VERSION 5.8 ;
BUSBITCHARS "[]" ;
DIVIDERCHAR "/" ;
UNITS
    DATABASE MICRONS 1000 ;
END UNITS

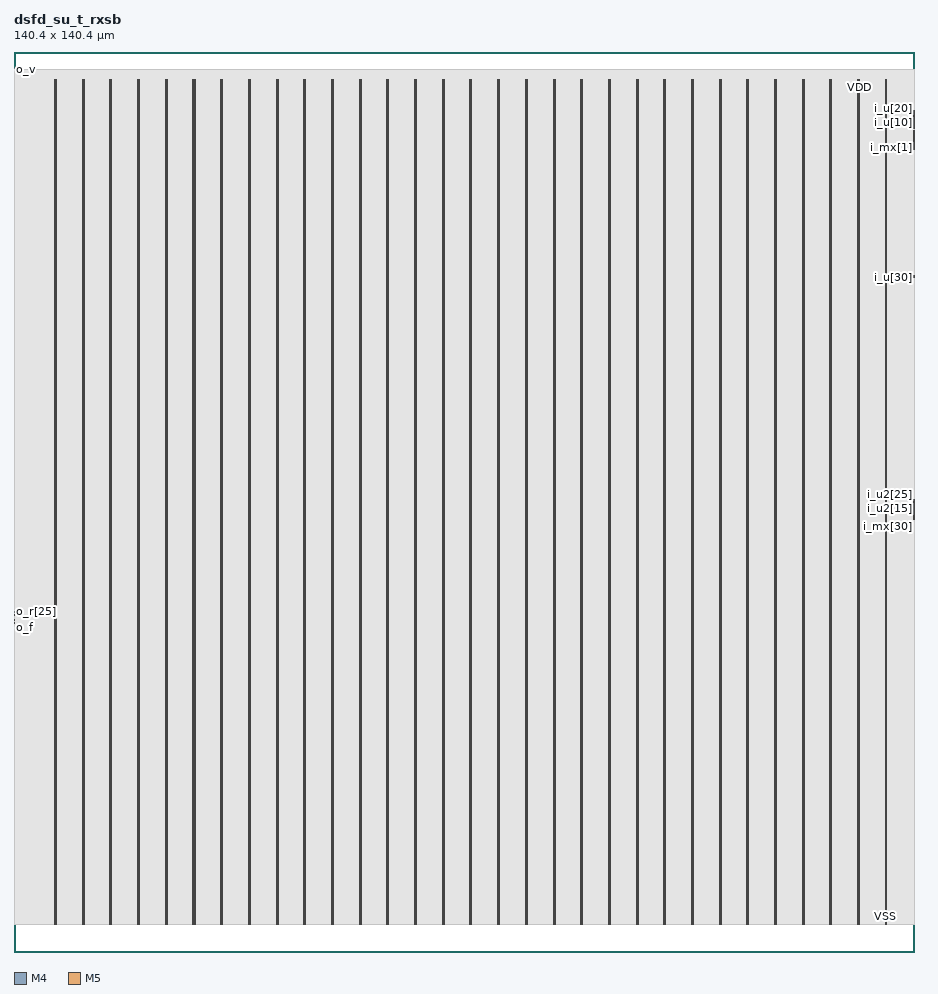
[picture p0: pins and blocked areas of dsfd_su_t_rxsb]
MACRO dsfd_su_t_rxsb
  FOREIGN dsfd_su_t_rxsb 0 0 ;
  CLASS BLOCK ;
  SIZE 140.4 BY 140.4 ;
  PIN ck
    DIRECTION INPUT ;
    USE SIGNAL ;
    PORT
      LAYER M4 ;
        RECT  140.316 125.136 140.4 125.16 ;
    END
  END ck
  PIN i_f
    DIRECTION INPUT ;
    USE SIGNAL ;
    PORT
      LAYER M4 ;
        RECT  140.316 125.232 140.4 125.256 ;
    END
  END i_f
  PIN i_mx[0]
    DIRECTION INPUT ;
    USE SIGNAL ;
    PORT
      LAYER M4 ;
        RECT  140.316 125.328 140.4 125.352 ;
    END
  END i_mx[0]
  PIN i_mx[10]
    DIRECTION INPUT ;
    USE SIGNAL ;
    PORT
      LAYER M4 ;
        RECT  140.316 126.288 140.4 126.312 ;
    END
  END i_mx[10]
  PIN i_mx[11]
    DIRECTION INPUT ;
    USE SIGNAL ;
    PORT
      LAYER M4 ;
        RECT  140.316 126.384 140.4 126.408 ;
    END
  END i_mx[11]
  PIN i_mx[12]
    DIRECTION INPUT ;
    USE SIGNAL ;
    PORT
      LAYER M4 ;
        RECT  140.316 126.48 140.4 126.504 ;
    END
  END i_mx[12]
  PIN i_mx[13]
    DIRECTION INPUT ;
    USE SIGNAL ;
    PORT
      LAYER M4 ;
        RECT  140.316 126.576 140.4 126.6 ;
    END
  END i_mx[13]
  PIN i_mx[14]
    DIRECTION INPUT ;
    USE SIGNAL ;
    PORT
      LAYER M4 ;
        RECT  140.316 126.672 140.4 126.696 ;
    END
  END i_mx[14]
  PIN i_mx[15]
    DIRECTION INPUT ;
    USE SIGNAL ;
    PORT
      LAYER M4 ;
        RECT  140.316 126.768 140.4 126.792 ;
    END
  END i_mx[15]
  PIN i_mx[16]
    DIRECTION INPUT ;
    USE SIGNAL ;
    PORT
      LAYER M4 ;
        RECT  140.316 126.864 140.4 126.888 ;
    END
  END i_mx[16]
  PIN i_mx[17]
    DIRECTION INPUT ;
    USE SIGNAL ;
    PORT
      LAYER M4 ;
        RECT  140.316 126.96 140.4 126.984 ;
    END
  END i_mx[17]
  PIN i_mx[18]
    DIRECTION INPUT ;
    USE SIGNAL ;
    PORT
      LAYER M4 ;
        RECT  140.316 127.056 140.4 127.08 ;
    END
  END i_mx[18]
  PIN i_mx[19]
    DIRECTION INPUT ;
    USE SIGNAL ;
    PORT
      LAYER M4 ;
        RECT  140.316 127.152 140.4 127.176 ;
    END
  END i_mx[19]
  PIN i_mx[1]
    DIRECTION INPUT ;
    USE SIGNAL ;
    PORT
      LAYER M4 ;
        RECT  140.316 125.424 140.4 125.448 ;
    END
  END i_mx[1]
  PIN i_mx[20]
    DIRECTION INPUT ;
    USE SIGNAL ;
    PORT
      LAYER M4 ;
        RECT  140.316 127.248 140.4 127.272 ;
    END
  END i_mx[20]
  PIN i_mx[21]
    DIRECTION INPUT ;
    USE SIGNAL ;
    PORT
      LAYER M4 ;
        RECT  140.316 127.344 140.4 127.368 ;
    END
  END i_mx[21]
  PIN i_mx[22]
    DIRECTION INPUT ;
    USE SIGNAL ;
    PORT
      LAYER M4 ;
        RECT  140.316 127.44 140.4 127.464 ;
    END
  END i_mx[22]
  PIN i_mx[23]
    DIRECTION INPUT ;
    USE SIGNAL ;
    PORT
      LAYER M4 ;
        RECT  140.316 127.536 140.4 127.56 ;
    END
  END i_mx[23]
  PIN i_mx[24]
    DIRECTION INPUT ;
    USE SIGNAL ;
    PORT
      LAYER M4 ;
        RECT  140.316 127.632 140.4 127.656 ;
    END
  END i_mx[24]
  PIN i_mx[25]
    DIRECTION INPUT ;
    USE SIGNAL ;
    PORT
      LAYER M4 ;
        RECT  140.316 127.728 140.4 127.752 ;
    END
  END i_mx[25]
  PIN i_mx[26]
    DIRECTION INPUT ;
    USE SIGNAL ;
    PORT
      LAYER M4 ;
        RECT  140.316 127.824 140.4 127.848 ;
    END
  END i_mx[26]
  PIN i_mx[27]
    DIRECTION INPUT ;
    USE SIGNAL ;
    PORT
      LAYER M4 ;
        RECT  140.316 127.92 140.4 127.944 ;
    END
  END i_mx[27]
  PIN i_mx[28]
    DIRECTION INPUT ;
    USE SIGNAL ;
    PORT
      LAYER M4 ;
        RECT  140.316 128.016 140.4 128.04 ;
    END
  END i_mx[28]
  PIN i_mx[29]
    DIRECTION INPUT ;
    USE SIGNAL ;
    PORT
      LAYER M4 ;
        RECT  140.316 128.112 140.4 128.136 ;
    END
  END i_mx[29]
  PIN i_mx[2]
    DIRECTION INPUT ;
    USE SIGNAL ;
    PORT
      LAYER M4 ;
        RECT  140.316 125.52 140.4 125.544 ;
    END
  END i_mx[2]
  PIN i_mx[30]
    DIRECTION INPUT ;
    USE SIGNAL ;
    PORT
      LAYER M4 ;
        RECT  140.316 67.536 140.4 67.56 ;
    END
  END i_mx[30]
  PIN i_mx[31]
    DIRECTION INPUT ;
    USE SIGNAL ;
    PORT
      LAYER M4 ;
        RECT  140.316 67.632 140.4 67.656 ;
    END
  END i_mx[31]
  PIN i_mx[3]
    DIRECTION INPUT ;
    USE SIGNAL ;
    PORT
      LAYER M4 ;
        RECT  140.316 125.616 140.4 125.64 ;
    END
  END i_mx[3]
  PIN i_mx[4]
    DIRECTION INPUT ;
    USE SIGNAL ;
    PORT
      LAYER M4 ;
        RECT  140.316 125.712 140.4 125.736 ;
    END
  END i_mx[4]
  PIN i_mx[5]
    DIRECTION INPUT ;
    USE SIGNAL ;
    PORT
      LAYER M4 ;
        RECT  140.316 125.808 140.4 125.832 ;
    END
  END i_mx[5]
  PIN i_mx[6]
    DIRECTION INPUT ;
    USE SIGNAL ;
    PORT
      LAYER M4 ;
        RECT  140.316 125.904 140.4 125.928 ;
    END
  END i_mx[6]
  PIN i_mx[7]
    DIRECTION INPUT ;
    USE SIGNAL ;
    PORT
      LAYER M4 ;
        RECT  140.316 126 140.4 126.024 ;
    END
  END i_mx[7]
  PIN i_mx[8]
    DIRECTION INPUT ;
    USE SIGNAL ;
    PORT
      LAYER M4 ;
        RECT  140.316 126.096 140.4 126.12 ;
    END
  END i_mx[8]
  PIN i_mx[9]
    DIRECTION INPUT ;
    USE SIGNAL ;
    PORT
      LAYER M4 ;
        RECT  140.316 126.192 140.4 126.216 ;
    END
  END i_mx[9]
  PIN i_u2[0]
    DIRECTION INPUT ;
    USE SIGNAL ;
    PORT
      LAYER M4 ;
        RECT  140.316 67.728 140.4 67.752 ;
    END
  END i_u2[0]
  PIN i_u2[10]
    DIRECTION INPUT ;
    USE SIGNAL ;
    PORT
      LAYER M4 ;
        RECT  140.316 68.688 140.4 68.712 ;
    END
  END i_u2[10]
  PIN i_u2[11]
    DIRECTION INPUT ;
    USE SIGNAL ;
    PORT
      LAYER M4 ;
        RECT  140.316 68.784 140.4 68.808 ;
    END
  END i_u2[11]
  PIN i_u2[12]
    DIRECTION INPUT ;
    USE SIGNAL ;
    PORT
      LAYER M4 ;
        RECT  140.316 68.88 140.4 68.904 ;
    END
  END i_u2[12]
  PIN i_u2[13]
    DIRECTION INPUT ;
    USE SIGNAL ;
    PORT
      LAYER M4 ;
        RECT  140.316 68.976 140.4 69 ;
    END
  END i_u2[13]
  PIN i_u2[14]
    DIRECTION INPUT ;
    USE SIGNAL ;
    PORT
      LAYER M4 ;
        RECT  140.316 69.072 140.4 69.096 ;
    END
  END i_u2[14]
  PIN i_u2[15]
    DIRECTION INPUT ;
    USE SIGNAL ;
    PORT
      LAYER M4 ;
        RECT  140.316 69.168 140.4 69.192 ;
    END
  END i_u2[15]
  PIN i_u2[16]
    DIRECTION INPUT ;
    USE SIGNAL ;
    PORT
      LAYER M4 ;
        RECT  140.316 69.264 140.4 69.288 ;
    END
  END i_u2[16]
  PIN i_u2[17]
    DIRECTION INPUT ;
    USE SIGNAL ;
    PORT
      LAYER M4 ;
        RECT  140.316 69.36 140.4 69.384 ;
    END
  END i_u2[17]
  PIN i_u2[18]
    DIRECTION INPUT ;
    USE SIGNAL ;
    PORT
      LAYER M4 ;
        RECT  140.316 69.456 140.4 69.48 ;
    END
  END i_u2[18]
  PIN i_u2[19]
    DIRECTION INPUT ;
    USE SIGNAL ;
    PORT
      LAYER M4 ;
        RECT  140.316 69.552 140.4 69.576 ;
    END
  END i_u2[19]
  PIN i_u2[1]
    DIRECTION INPUT ;
    USE SIGNAL ;
    PORT
      LAYER M4 ;
        RECT  140.316 67.824 140.4 67.848 ;
    END
  END i_u2[1]
  PIN i_u2[20]
    DIRECTION INPUT ;
    USE SIGNAL ;
    PORT
      LAYER M4 ;
        RECT  140.316 69.648 140.4 69.672 ;
    END
  END i_u2[20]
  PIN i_u2[21]
    DIRECTION INPUT ;
    USE SIGNAL ;
    PORT
      LAYER M4 ;
        RECT  140.316 69.744 140.4 69.768 ;
    END
  END i_u2[21]
  PIN i_u2[22]
    DIRECTION INPUT ;
    USE SIGNAL ;
    PORT
      LAYER M4 ;
        RECT  140.316 69.84 140.4 69.864 ;
    END
  END i_u2[22]
  PIN i_u2[23]
    DIRECTION INPUT ;
    USE SIGNAL ;
    PORT
      LAYER M4 ;
        RECT  140.316 69.936 140.4 69.96 ;
    END
  END i_u2[23]
  PIN i_u2[24]
    DIRECTION INPUT ;
    USE SIGNAL ;
    PORT
      LAYER M4 ;
        RECT  140.316 70.032 140.4 70.056 ;
    END
  END i_u2[24]
  PIN i_u2[25]
    DIRECTION INPUT ;
    USE SIGNAL ;
    PORT
      LAYER M4 ;
        RECT  140.316 70.128 140.4 70.152 ;
    END
  END i_u2[25]
  PIN i_u2[26]
    DIRECTION INPUT ;
    USE SIGNAL ;
    PORT
      LAYER M4 ;
        RECT  140.316 70.224 140.4 70.248 ;
    END
  END i_u2[26]
  PIN i_u2[27]
    DIRECTION INPUT ;
    USE SIGNAL ;
    PORT
      LAYER M4 ;
        RECT  140.316 70.32 140.4 70.344 ;
    END
  END i_u2[27]
  PIN i_u2[28]
    DIRECTION INPUT ;
    USE SIGNAL ;
    PORT
      LAYER M4 ;
        RECT  140.316 70.416 140.4 70.44 ;
    END
  END i_u2[28]
  PIN i_u2[29]
    DIRECTION INPUT ;
    USE SIGNAL ;
    PORT
      LAYER M4 ;
        RECT  140.316 70.512 140.4 70.536 ;
    END
  END i_u2[29]
  PIN i_u2[2]
    DIRECTION INPUT ;
    USE SIGNAL ;
    PORT
      LAYER M4 ;
        RECT  140.316 67.92 140.4 67.944 ;
    END
  END i_u2[2]
  PIN i_u2[30]
    DIRECTION INPUT ;
    USE SIGNAL ;
    PORT
      LAYER M4 ;
        RECT  140.316 128.208 140.4 128.232 ;
    END
  END i_u2[30]
  PIN i_u2[3]
    DIRECTION INPUT ;
    USE SIGNAL ;
    PORT
      LAYER M4 ;
        RECT  140.316 68.016 140.4 68.04 ;
    END
  END i_u2[3]
  PIN i_u2[4]
    DIRECTION INPUT ;
    USE SIGNAL ;
    PORT
      LAYER M4 ;
        RECT  140.316 68.112 140.4 68.136 ;
    END
  END i_u2[4]
  PIN i_u2[5]
    DIRECTION INPUT ;
    USE SIGNAL ;
    PORT
      LAYER M4 ;
        RECT  140.316 68.208 140.4 68.232 ;
    END
  END i_u2[5]
  PIN i_u2[6]
    DIRECTION INPUT ;
    USE SIGNAL ;
    PORT
      LAYER M4 ;
        RECT  140.316 68.304 140.4 68.328 ;
    END
  END i_u2[6]
  PIN i_u2[7]
    DIRECTION INPUT ;
    USE SIGNAL ;
    PORT
      LAYER M4 ;
        RECT  140.316 68.4 140.4 68.424 ;
    END
  END i_u2[7]
  PIN i_u2[8]
    DIRECTION INPUT ;
    USE SIGNAL ;
    PORT
      LAYER M4 ;
        RECT  140.316 68.496 140.4 68.52 ;
    END
  END i_u2[8]
  PIN i_u2[9]
    DIRECTION INPUT ;
    USE SIGNAL ;
    PORT
      LAYER M4 ;
        RECT  140.316 68.592 140.4 68.616 ;
    END
  END i_u2[9]
  PIN i_u[0]
    DIRECTION INPUT ;
    USE SIGNAL ;
    PORT
      LAYER M4 ;
        RECT  140.316 128.4 140.4 128.424 ;
    END
  END i_u[0]
  PIN i_u[10]
    DIRECTION INPUT ;
    USE SIGNAL ;
    PORT
      LAYER M4 ;
        RECT  140.316 129.36 140.4 129.384 ;
    END
  END i_u[10]
  PIN i_u[11]
    DIRECTION INPUT ;
    USE SIGNAL ;
    PORT
      LAYER M4 ;
        RECT  140.316 129.456 140.4 129.48 ;
    END
  END i_u[11]
  PIN i_u[12]
    DIRECTION INPUT ;
    USE SIGNAL ;
    PORT
      LAYER M4 ;
        RECT  140.316 129.552 140.4 129.576 ;
    END
  END i_u[12]
  PIN i_u[13]
    DIRECTION INPUT ;
    USE SIGNAL ;
    PORT
      LAYER M4 ;
        RECT  140.316 129.648 140.4 129.672 ;
    END
  END i_u[13]
  PIN i_u[14]
    DIRECTION INPUT ;
    USE SIGNAL ;
    PORT
      LAYER M4 ;
        RECT  140.316 129.744 140.4 129.768 ;
    END
  END i_u[14]
  PIN i_u[15]
    DIRECTION INPUT ;
    USE SIGNAL ;
    PORT
      LAYER M4 ;
        RECT  140.316 129.84 140.4 129.864 ;
    END
  END i_u[15]
  PIN i_u[16]
    DIRECTION INPUT ;
    USE SIGNAL ;
    PORT
      LAYER M4 ;
        RECT  140.316 129.936 140.4 129.96 ;
    END
  END i_u[16]
  PIN i_u[17]
    DIRECTION INPUT ;
    USE SIGNAL ;
    PORT
      LAYER M4 ;
        RECT  140.316 130.032 140.4 130.056 ;
    END
  END i_u[17]
  PIN i_u[18]
    DIRECTION INPUT ;
    USE SIGNAL ;
    PORT
      LAYER M4 ;
        RECT  140.316 130.128 140.4 130.152 ;
    END
  END i_u[18]
  PIN i_u[19]
    DIRECTION INPUT ;
    USE SIGNAL ;
    PORT
      LAYER M4 ;
        RECT  140.316 130.224 140.4 130.248 ;
    END
  END i_u[19]
  PIN i_u[1]
    DIRECTION INPUT ;
    USE SIGNAL ;
    PORT
      LAYER M4 ;
        RECT  140.316 128.496 140.4 128.52 ;
    END
  END i_u[1]
  PIN i_u[20]
    DIRECTION INPUT ;
    USE SIGNAL ;
    PORT
      LAYER M4 ;
        RECT  140.316 130.32 140.4 130.344 ;
    END
  END i_u[20]
  PIN i_u[21]
    DIRECTION INPUT ;
    USE SIGNAL ;
    PORT
      LAYER M4 ;
        RECT  140.316 130.416 140.4 130.44 ;
    END
  END i_u[21]
  PIN i_u[22]
    DIRECTION INPUT ;
    USE SIGNAL ;
    PORT
      LAYER M4 ;
        RECT  140.316 130.512 140.4 130.536 ;
    END
  END i_u[22]
  PIN i_u[23]
    DIRECTION INPUT ;
    USE SIGNAL ;
    PORT
      LAYER M4 ;
        RECT  140.316 130.608 140.4 130.632 ;
    END
  END i_u[23]
  PIN i_u[24]
    DIRECTION INPUT ;
    USE SIGNAL ;
    PORT
      LAYER M4 ;
        RECT  140.316 130.704 140.4 130.728 ;
    END
  END i_u[24]
  PIN i_u[25]
    DIRECTION INPUT ;
    USE SIGNAL ;
    PORT
      LAYER M4 ;
        RECT  140.316 130.8 140.4 130.824 ;
    END
  END i_u[25]
  PIN i_u[26]
    DIRECTION INPUT ;
    USE SIGNAL ;
    PORT
      LAYER M4 ;
        RECT  140.316 130.896 140.4 130.92 ;
    END
  END i_u[26]
  PIN i_u[27]
    DIRECTION INPUT ;
    USE SIGNAL ;
    PORT
      LAYER M4 ;
        RECT  140.316 130.992 140.4 131.016 ;
    END
  END i_u[27]
  PIN i_u[28]
    DIRECTION INPUT ;
    USE SIGNAL ;
    PORT
      LAYER M4 ;
        RECT  140.316 131.088 140.4 131.112 ;
    END
  END i_u[28]
  PIN i_u[29]
    DIRECTION INPUT ;
    USE SIGNAL ;
    PORT
      LAYER M4 ;
        RECT  140.316 131.184 140.4 131.208 ;
    END
  END i_u[29]
  PIN i_u[2]
    DIRECTION INPUT ;
    USE SIGNAL ;
    PORT
      LAYER M4 ;
        RECT  140.316 128.592 140.4 128.616 ;
    END
  END i_u[2]
  PIN i_u[30]
    DIRECTION INPUT ;
    USE SIGNAL ;
    PORT
      LAYER M4 ;
        RECT  140.316 105.168 140.4 105.192 ;
    END
  END i_u[30]
  PIN i_u[3]
    DIRECTION INPUT ;
    USE SIGNAL ;
    PORT
      LAYER M4 ;
        RECT  140.316 128.688 140.4 128.712 ;
    END
  END i_u[3]
  PIN i_u[4]
    DIRECTION INPUT ;
    USE SIGNAL ;
    PORT
      LAYER M4 ;
        RECT  140.316 128.784 140.4 128.808 ;
    END
  END i_u[4]
  PIN i_u[5]
    DIRECTION INPUT ;
    USE SIGNAL ;
    PORT
      LAYER M4 ;
        RECT  140.316 128.88 140.4 128.904 ;
    END
  END i_u[5]
  PIN i_u[6]
    DIRECTION INPUT ;
    USE SIGNAL ;
    PORT
      LAYER M4 ;
        RECT  140.316 128.976 140.4 129 ;
    END
  END i_u[6]
  PIN i_u[7]
    DIRECTION INPUT ;
    USE SIGNAL ;
    PORT
      LAYER M4 ;
        RECT  140.316 129.072 140.4 129.096 ;
    END
  END i_u[7]
  PIN i_u[8]
    DIRECTION INPUT ;
    USE SIGNAL ;
    PORT
      LAYER M4 ;
        RECT  140.316 129.168 140.4 129.192 ;
    END
  END i_u[8]
  PIN i_u[9]
    DIRECTION INPUT ;
    USE SIGNAL ;
    PORT
      LAYER M4 ;
        RECT  140.316 129.264 140.4 129.288 ;
    END
  END i_u[9]
  PIN i_v
    DIRECTION INPUT ;
    USE SIGNAL ;
    PORT
      LAYER M4 ;
        RECT  140.316 105.36 140.4 105.384 ;
    END
  END i_v
  PIN o_f
    DIRECTION OUTPUT ;
    USE SIGNAL ;
    PORT
      LAYER M4 ;
        RECT  0 50.64 0.084 50.664 ;
    END
  END o_f
  PIN o_r[0]
    DIRECTION OUTPUT ;
    USE SIGNAL ;
    PORT
      LAYER M4 ;
        RECT  0 50.736 0.084 50.76 ;
    END
  END o_r[0]
  PIN o_r[10]
    DIRECTION OUTPUT ;
    USE SIGNAL ;
    PORT
      LAYER M4 ;
        RECT  0 51.696 0.084 51.72 ;
    END
  END o_r[10]
  PIN o_r[11]
    DIRECTION OUTPUT ;
    USE SIGNAL ;
    PORT
      LAYER M4 ;
        RECT  0 51.792 0.084 51.816 ;
    END
  END o_r[11]
  PIN o_r[12]
    DIRECTION OUTPUT ;
    USE SIGNAL ;
    PORT
      LAYER M4 ;
        RECT  0 51.888 0.084 51.912 ;
    END
  END o_r[12]
  PIN o_r[13]
    DIRECTION OUTPUT ;
    USE SIGNAL ;
    PORT
      LAYER M4 ;
        RECT  0 51.984 0.084 52.008 ;
    END
  END o_r[13]
  PIN o_r[14]
    DIRECTION OUTPUT ;
    USE SIGNAL ;
    PORT
      LAYER M4 ;
        RECT  0 52.08 0.084 52.104 ;
    END
  END o_r[14]
  PIN o_r[15]
    DIRECTION OUTPUT ;
    USE SIGNAL ;
    PORT
      LAYER M4 ;
        RECT  0 52.176 0.084 52.2 ;
    END
  END o_r[15]
  PIN o_r[16]
    DIRECTION OUTPUT ;
    USE SIGNAL ;
    PORT
      LAYER M4 ;
        RECT  0 52.272 0.084 52.296 ;
    END
  END o_r[16]
  PIN o_r[17]
    DIRECTION OUTPUT ;
    USE SIGNAL ;
    PORT
      LAYER M4 ;
        RECT  0 52.368 0.084 52.392 ;
    END
  END o_r[17]
  PIN o_r[18]
    DIRECTION OUTPUT ;
    USE SIGNAL ;
    PORT
      LAYER M4 ;
        RECT  0 52.464 0.084 52.488 ;
    END
  END o_r[18]
  PIN o_r[19]
    DIRECTION OUTPUT ;
    USE SIGNAL ;
    PORT
      LAYER M4 ;
        RECT  0 52.56 0.084 52.584 ;
    END
  END o_r[19]
  PIN o_r[1]
    DIRECTION OUTPUT ;
    USE SIGNAL ;
    PORT
      LAYER M4 ;
        RECT  0 50.832 0.084 50.856 ;
    END
  END o_r[1]
  PIN o_r[20]
    DIRECTION OUTPUT ;
    USE SIGNAL ;
    PORT
      LAYER M4 ;
        RECT  0 52.656 0.084 52.68 ;
    END
  END o_r[20]
  PIN o_r[21]
    DIRECTION OUTPUT ;
    USE SIGNAL ;
    PORT
      LAYER M4 ;
        RECT  0 52.752 0.084 52.776 ;
    END
  END o_r[21]
  PIN o_r[22]
    DIRECTION OUTPUT ;
    USE SIGNAL ;
    PORT
      LAYER M4 ;
        RECT  0 52.848 0.084 52.872 ;
    END
  END o_r[22]
  PIN o_r[23]
    DIRECTION OUTPUT ;
    USE SIGNAL ;
    PORT
      LAYER M4 ;
        RECT  0 52.944 0.084 52.968 ;
    END
  END o_r[23]
  PIN o_r[24]
    DIRECTION OUTPUT ;
    USE SIGNAL ;
    PORT
      LAYER M4 ;
        RECT  0 53.04 0.084 53.064 ;
    END
  END o_r[24]
  PIN o_r[25]
    DIRECTION OUTPUT ;
    USE SIGNAL ;
    PORT
      LAYER M4 ;
        RECT  0 53.136 0.084 53.16 ;
    END
  END o_r[25]
  PIN o_r[26]
    DIRECTION OUTPUT ;
    USE SIGNAL ;
    PORT
      LAYER M4 ;
        RECT  0 53.232 0.084 53.256 ;
    END
  END o_r[26]
  PIN o_r[27]
    DIRECTION OUTPUT ;
    USE SIGNAL ;
    PORT
      LAYER M4 ;
        RECT  0 53.328 0.084 53.352 ;
    END
  END o_r[27]
  PIN o_r[28]
    DIRECTION OUTPUT ;
    USE SIGNAL ;
    PORT
      LAYER M4 ;
        RECT  0 53.424 0.084 53.448 ;
    END
  END o_r[28]
  PIN o_r[29]
    DIRECTION OUTPUT ;
    USE SIGNAL ;
    PORT
      LAYER M4 ;
        RECT  0 53.52 0.084 53.544 ;
    END
  END o_r[29]
  PIN o_r[2]
    DIRECTION OUTPUT ;
    USE SIGNAL ;
    PORT
      LAYER M4 ;
        RECT  0 50.928 0.084 50.952 ;
    END
  END o_r[2]
  PIN o_r[30]
    DIRECTION OUTPUT ;
    USE SIGNAL ;
    PORT
      LAYER M4 ;
        RECT  0 53.616 0.084 53.64 ;
    END
  END o_r[30]
  PIN o_r[3]
    DIRECTION OUTPUT ;
    USE SIGNAL ;
    PORT
      LAYER M4 ;
        RECT  0 51.024 0.084 51.048 ;
    END
  END o_r[3]
  PIN o_r[4]
    DIRECTION OUTPUT ;
    USE SIGNAL ;
    PORT
      LAYER M4 ;
        RECT  0 51.12 0.084 51.144 ;
    END
  END o_r[4]
  PIN o_r[5]
    DIRECTION OUTPUT ;
    USE SIGNAL ;
    PORT
      LAYER M4 ;
        RECT  0 51.216 0.084 51.24 ;
    END
  END o_r[5]
  PIN o_r[6]
    DIRECTION OUTPUT ;
    USE SIGNAL ;
    PORT
      LAYER M4 ;
        RECT  0 51.312 0.084 51.336 ;
    END
  END o_r[6]
  PIN o_r[7]
    DIRECTION OUTPUT ;
    USE SIGNAL ;
    PORT
      LAYER M4 ;
        RECT  0 51.408 0.084 51.432 ;
    END
  END o_r[7]
  PIN o_r[8]
    DIRECTION OUTPUT ;
    USE SIGNAL ;
    PORT
      LAYER M4 ;
        RECT  0 51.504 0.084 51.528 ;
    END
  END o_r[8]
  PIN o_r[9]
    DIRECTION OUTPUT ;
    USE SIGNAL ;
    PORT
      LAYER M4 ;
        RECT  0 51.6 0.084 51.624 ;
    END
  END o_r[9]
  PIN o_v
    DIRECTION OUTPUT ;
    USE SIGNAL ;
    PORT
      LAYER M4 ;
        RECT  0 137.712 0.084 137.736 ;
    END
  END o_v
  PIN rst
    DIRECTION INPUT ;
    USE SIGNAL ;
    PORT
      LAYER M4 ;
        RECT  140.316 105.456 140.4 105.48 ;
    END
  END rst
  PIN VDD
    DIRECTION INOUT ;
    USE POWER ;
    PORT
      LAYER M5 ;
        RECT  131.796 4.311 131.916 136.089 ;
        RECT  127.476 4.311 127.596 136.089 ;
        RECT  123.156 4.311 123.276 136.089 ;
        RECT  118.836 4.311 118.956 136.089 ;
        RECT  114.516 4.311 114.636 136.089 ;
        RECT  110.196 4.311 110.316 136.089 ;
        RECT  105.876 4.311 105.996 136.089 ;
        RECT  101.556 4.311 101.676 136.089 ;
        RECT  97.236 4.311 97.356 136.089 ;
        RECT  92.916 4.311 93.036 136.089 ;
        RECT  88.596 4.311 88.716 136.089 ;
        RECT  84.276 4.311 84.396 136.089 ;
        RECT  79.956 4.311 80.076 136.089 ;
        RECT  75.636 4.311 75.756 136.089 ;
        RECT  71.316 4.311 71.436 136.089 ;
        RECT  66.996 4.311 67.116 136.089 ;
        RECT  62.676 4.311 62.796 136.089 ;
        RECT  58.356 4.311 58.476 136.089 ;
        RECT  54.036 4.311 54.156 136.089 ;
        RECT  49.716 4.311 49.836 136.089 ;
        RECT  45.396 4.311 45.516 136.089 ;
        RECT  41.076 4.311 41.196 136.089 ;
        RECT  36.756 4.311 36.876 136.089 ;
        RECT  32.436 4.311 32.556 136.089 ;
        RECT  28.116 4.311 28.236 136.089 ;
        RECT  23.796 4.311 23.916 136.089 ;
        RECT  19.476 4.311 19.596 136.089 ;
        RECT  15.156 4.311 15.276 136.089 ;
        RECT  10.836 4.311 10.956 136.089 ;
        RECT  6.516 4.311 6.636 136.089 ;
    END
  END VDD
  PIN VSS
    DIRECTION INOUT ;
    USE GROUND ;
    PORT
      LAYER M5 ;
        RECT  135.924 4.297 136.044 136.103 ;
        RECT  131.604 4.297 131.724 136.103 ;
        RECT  127.284 4.297 127.404 136.103 ;
        RECT  122.964 4.297 123.084 136.103 ;
        RECT  118.644 4.297 118.764 136.103 ;
        RECT  114.324 4.297 114.444 136.103 ;
        RECT  110.004 4.297 110.124 136.103 ;
        RECT  105.684 4.297 105.804 136.103 ;
        RECT  101.364 4.297 101.484 136.103 ;
        RECT  97.044 4.297 97.164 136.103 ;
        RECT  92.724 4.297 92.844 136.103 ;
        RECT  88.404 4.297 88.524 136.103 ;
        RECT  84.084 4.297 84.204 136.103 ;
        RECT  79.764 4.297 79.884 136.103 ;
        RECT  75.444 4.297 75.564 136.103 ;
        RECT  71.124 4.297 71.244 136.103 ;
        RECT  66.804 4.297 66.924 136.103 ;
        RECT  62.484 4.297 62.604 136.103 ;
        RECT  58.164 4.297 58.284 136.103 ;
        RECT  53.844 4.297 53.964 136.103 ;
        RECT  49.524 4.297 49.644 136.103 ;
        RECT  45.204 4.297 45.324 136.103 ;
        RECT  40.884 4.297 41.004 136.103 ;
        RECT  36.564 4.297 36.684 136.103 ;
        RECT  32.244 4.297 32.364 136.103 ;
        RECT  27.924 4.297 28.044 136.103 ;
        RECT  23.604 4.297 23.724 136.103 ;
        RECT  19.284 4.297 19.404 136.103 ;
        RECT  14.964 4.297 15.084 136.103 ;
        RECT  10.644 4.297 10.764 136.103 ;
        RECT  6.324 4.297 6.444 136.103 ;
    END
  END VSS
  OBS
    LAYER RVTN ;
     RECT  0 4.261 140.4 137.741 ;
    LAYER RVTP ;
     RECT  0 4.261 140.4 137.741 ;
    LAYER M1 ;
     RECT  0 4.261 140.4 137.741 ;
    LAYER M2 ;
     RECT  0 4.261 140.4 137.741 ;
    LAYER M3 ;
     RECT  0 4.261 140.4 137.741 ;
    LAYER M4 ;
     RECT  0 4.261 140.4 137.741 ;
    LAYER M5 ;
     RECT  0 4.261 140.4 137.741 ;
  END
END dsfd_su_t_rxsb
END LIBRARY
